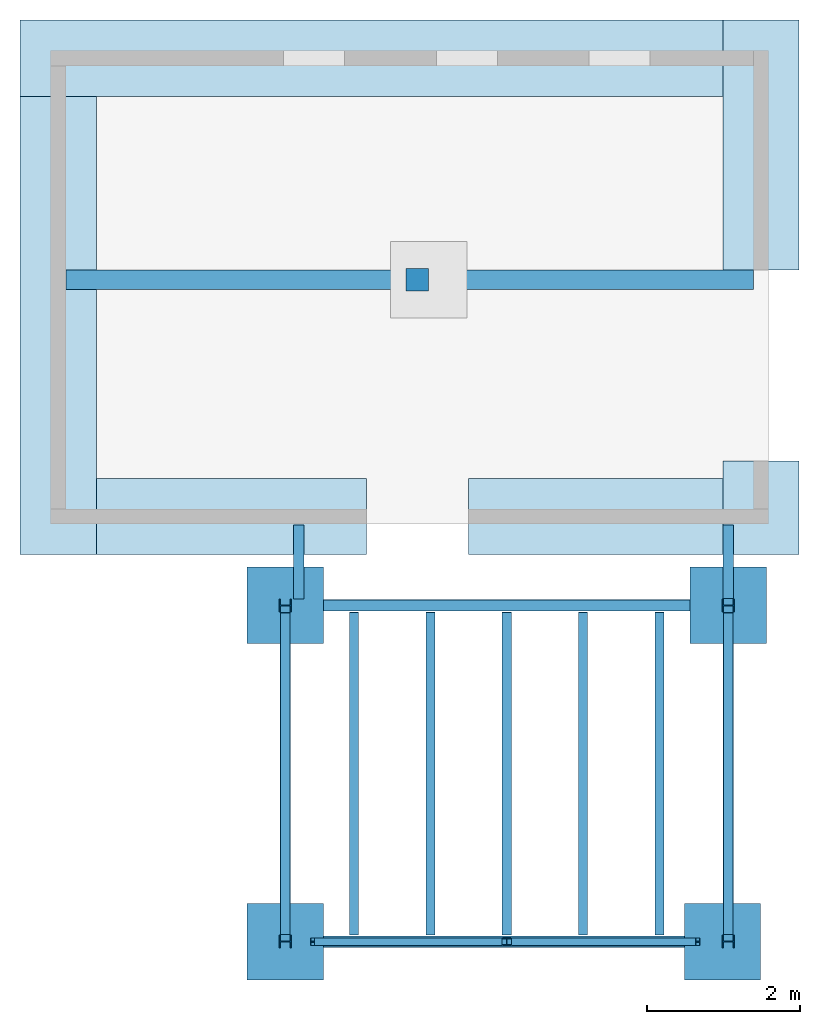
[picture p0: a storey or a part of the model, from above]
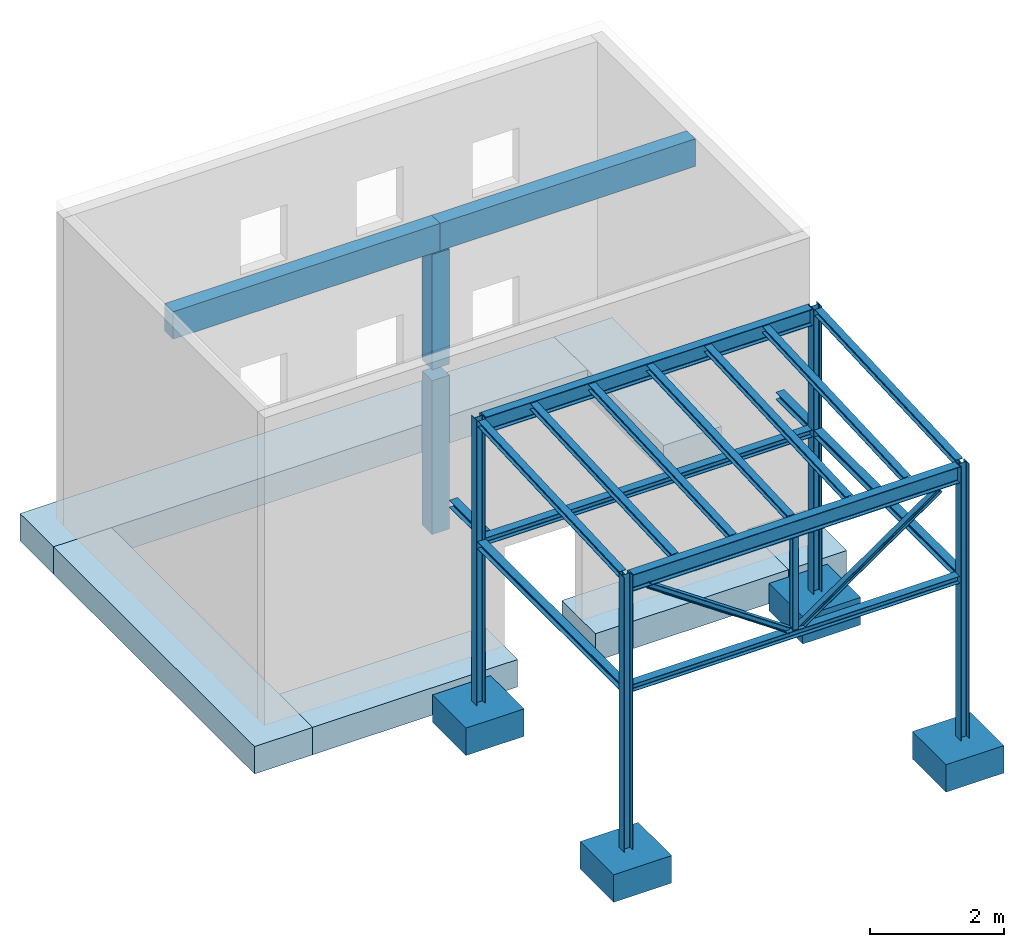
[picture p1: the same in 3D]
Properties of the parts of a building model (IFC2X3)

# File
Description: ViewDefinition [CoordinationView_V2.0]
File name: 2018_01
Time: 2019-08-13T11:54:30
Written by: The EXPRESS Data Manager Version 5.02.0100.07 : 28 Aug 2013
Made in: 20190327_2315(x64) - Exporter 20.0.0.377 - Alternativ-UI 20.0.0.377
Comment: STEP Physical File produced by: The EXPRESS Data Manager Version 5.02.0100.07 : 28 Aug 2013 * Module: EDMstepFileFactory/EDMstandAlone * Creation date: Tue Aug 13 11:54:30 2019 * Host: SuehnelL-PC1 * Database: C:\Users\SUEHNE~1.DLU\AppData\Local\Temp\6addadaa-6409-4b06-a7e4-3825f1259560\28d34ed8-b4bb-4808-aa8c-ddc9ad598f6a\ifc * Database version: 5507 * Database creation date: Tue Aug 13 11:54:28 2019 * Schema: IFC2X3 * Model: DataRepository.ifc * Model creation date: Tue Aug 13 11:54:29 2019 * Header model: DataRepository.ifc_HeaderModel * Header model creation date: Tue Aug 13 11:54:29 2019 * EDMuser: sdai-user * EDMgroup: sdai-group * License ID and type: 5605 : Permanent license. Expiry date: * EDMstepFileFactory options: 020000

# IfcProject, 2018_01
Phase: Projekt Status

# IfcSite, Default
RefLatitude: 48, 8, 15, 359802; RefLongitude: 11, 34, 47, 783432; RefElevation: 519 m

# IfcBuilding
Pset_BuildingCommon - NumberOfStoreys: 0

# IfcBeam: HEA 100 (2)
Type - PredefinedType: BEAM
Type - Pset_BeamCommon - IsExternal: no; Reference: HEA 100
Type - Pset_QuantityTakeOff - Reference: HEA 100
Type - Pset_ReinforcementBarPitchOfBeam - Reference: HEA 100
Material: Metall - Baustahl S235
Pset_QuantityTakeOff - sets with these values: 2
Name (HEA Träger:HEA 100:...) | Span (m) | Slope (deg)
2444262 | 3.5228 | 34.5921
2444790 | 3.5227 | 34.5932

# IfcBeam: HEA 120 (7)
Type - PredefinedType: BEAM
Type - Pset_BeamCommon - IsExternal: no; Reference: HEA 120
Type - Pset_QuantityTakeOff - Reference: HEA 120
Type - Pset_ReinforcementBarPitchOfBeam - Reference: HEA 120
Material: Metall - Baustahl S235
Pset_BeamCommon - Span: 4.4046 m; Slope: 2.60253 deg
Pset_QuantityTakeOff - sets with these values: 2
Name (HEA Träger:HEA 120:...)
2440952
2440991
2441722
2441823
2441839
2441855
2441869

# IfcBeam: HEA 140 (6)
Type - PredefinedType: BEAM
Type - Pset_BeamCommon - IsExternal: no; Reference: HEA 140
Type - Pset_QuantityTakeOff - Reference: HEA 140
Type - Pset_ReinforcementBarPitchOfBeam - Reference: HEA 140
Material: Metall - Baustahl S235
Pset_BeamCommon - Slope: 0 deg
Pset_QuantityTakeOff - sets with these values: 2
Name (HEA Träger:HEA 140:...) | Span (m)
2442064 | 5.8
2442155 | 5.8
2442526 | 4.4
2442927 | 4.4
2448989 | 1.0643
2449286 | 1.0643

# IfcBeam: IPE 300 (2)
Type - PredefinedType: BEAM
Type - Pset_BeamCommon - IsExternal: no; Reference: IPE 300
Type - Pset_QuantityTakeOff - Reference: IPE 300
Type - Pset_ReinforcementBarPitchOfBeam - Reference: IPE 300
Material: Metall - Baustahl S235
Pset_BeamCommon - Slope: 0 deg; Span: 5.8 m
Pset_QuantityTakeOff - sets with these values: 2
Name (IPE Träger:IPE 300:...)
2441045
2441087

# IfcBeam: STB 250 x 500 (2)
Type - PredefinedType: BEAM
Type - Pset_BeamCommon - IsExternal: no; Reference: STB 250 x 500
Type - Pset_QuantityTakeOff - Reference: STB 250 x 500
Type - Pset_ReinforcementBarPitchOfBeam - Reference: STB 250 x 500
Material: Ortbeton - bewehrt Verputzt
Pset_BeamCommon - Slope: 0 deg
Pset_QuantityTakeOff - sets with these values: 2
Name (STB Träger - rechteckig:STB 250 x 500:...) | Span (m)
2447766 | 4.5
2447836 | 4.7

# IfcColumn: HEA 100, HEA Stütze:HEA 100:2443765
Type - PredefinedType: COLUMN
Type - Pset_ColumnCommon - IsExternal: no; LoadBearing: yes; Reference: HEA 100
Type - Pset_QuantityTakeOff - Reference: HEA 100
Type - Pset_ReinforcementBarPitchOfColumn - Reference: HEA 100
Material: Metall - Baustahl S235
Pset_ColumnCommon - Slope: 0 deg
Pset_QuantityTakeOff - sets with these values: 2

# IfcColumn: HEA 160 (4)
Type - PredefinedType: COLUMN
Type - Pset_ColumnCommon - Reference: HEA 160; IsExternal: no; LoadBearing: yes
Type - Pset_QuantityTakeOff - Reference: HEA 160
Type - Pset_ReinforcementBarPitchOfColumn - Reference: HEA 160
Material: Metall - Baustahl S235
Pset_ColumnCommon - Slope: 0 deg
Pset_QuantityTakeOff - sets with these values: 2
Name (HEA Stütze:HEA 160:...)
2439713
2439955
2440402
2440629

# IfcColumn: STB 300 x 300 (2)
Type - PredefinedType: COLUMN
Type - Pset_ColumnCommon - IsExternal: no; LoadBearing: yes; Reference: STB 300 x 300
Type - Pset_QuantityTakeOff - Reference: STB 300 x 300
Type - Pset_ReinforcementBarPitchOfColumn - Reference: STB 300 x 300
Material: Ortbeton - bewehrt Verputzt
Pset_ColumnCommon - Slope: 0 deg
Pset_QuantityTakeOff - sets with these values: 2
Name (STB Stütze - rechteckig:STB 300 x 300:...)
2449820
2450037

# IfcFooting: Wandfundament:STB 1000 x 500 (4)
PredefinedType: STRIP_FOOTING; Material: Ortbeton - bewehrt
Pset_QuantityTakeOff - Reference: STB 1000 x 500; sets with these values: 3
Name (Wandfundament:STB 1000 x 500:...)
2446997
2447006
2447019
2447032

# IfcOpeningElement: Opening (8)
Pset_QuantityTakeOff - Reference: STB 200; sets with these values: 2
Name (Basiswand:STB 200:...)
2445920
2446085
6 x 2446182

# IfcSlab: Geschossdecke:STB 200 (2)
Type - PredefinedType: FLOOR; Material: Ortbeton - bewehrt 0.2 m
Type - Pset_QuantityTakeOff - Reference: STB 200
Type - Pset_ReinforcementBarPitchOfSlab - Reference: STB 200
Type - Pset_SlabCommon - IsExternal: no; Reference: STB 200; ThermalTransmittance: 5.23 kg/K/s3
Pset_QuantityTakeOff - sets with these values: 2
Pset_SlabCommon - LoadBearing: yes; PitchAngle: 0 deg
Name (Geschossdecke:STB 200:...)
2447113
2447163

# IfcSlab: STB 1800 x 1800 x 700 (5)
Type - PredefinedType: FLOOR
Type - Pset_QuantityTakeOff - Reference: STB 1800 x 1800 x 700
Type - Pset_ReinforcementBarPitchOfSlab - Reference: STB 1800 x 1800 x 700
Type - Pset_SlabCommon - IsExternal: no; Reference: STB 1800 x 1800 x 700
Pset_QuantityTakeOff - sets with these values: 2
Pset_SlabCommon - PitchAngle: 0 deg
Name (Einzelfundament:STB 1800 x 1800 x 700:...)
2448050
2448121
2448314
2448414
2450774

# IfcWallStandardCase: Basiswand:STB 200 (4)
Type - PredefinedType: STANDARD; Material: Ortbeton - bewehrt Verputzt 0.2 m
Type - Pset_QuantityTakeOff - Reference: STB 200
Type - Pset_ReinforcementBarPitchOfWall - Reference: STB 200
Type - Pset_WallCommon - IsExternal: no; Reference: STB 200; ThermalTransmittance: 5.23 kg/K/s3
Pset_QuantityTakeOff - sets with these values: 2
Pset_WallCommon - LoadBearing: yes; IsExternal: yes; ExtendToStructure: yes
Name (Basiswand:STB 200:...)
2445920
2446085
2446182
2446251
